VERSION 5.8 ;
BUSBITCHARS "[]" ;
DIVIDERCHAR "/" ;
UNITS
    DATABASE MICRONS 2000 ;
END UNITS

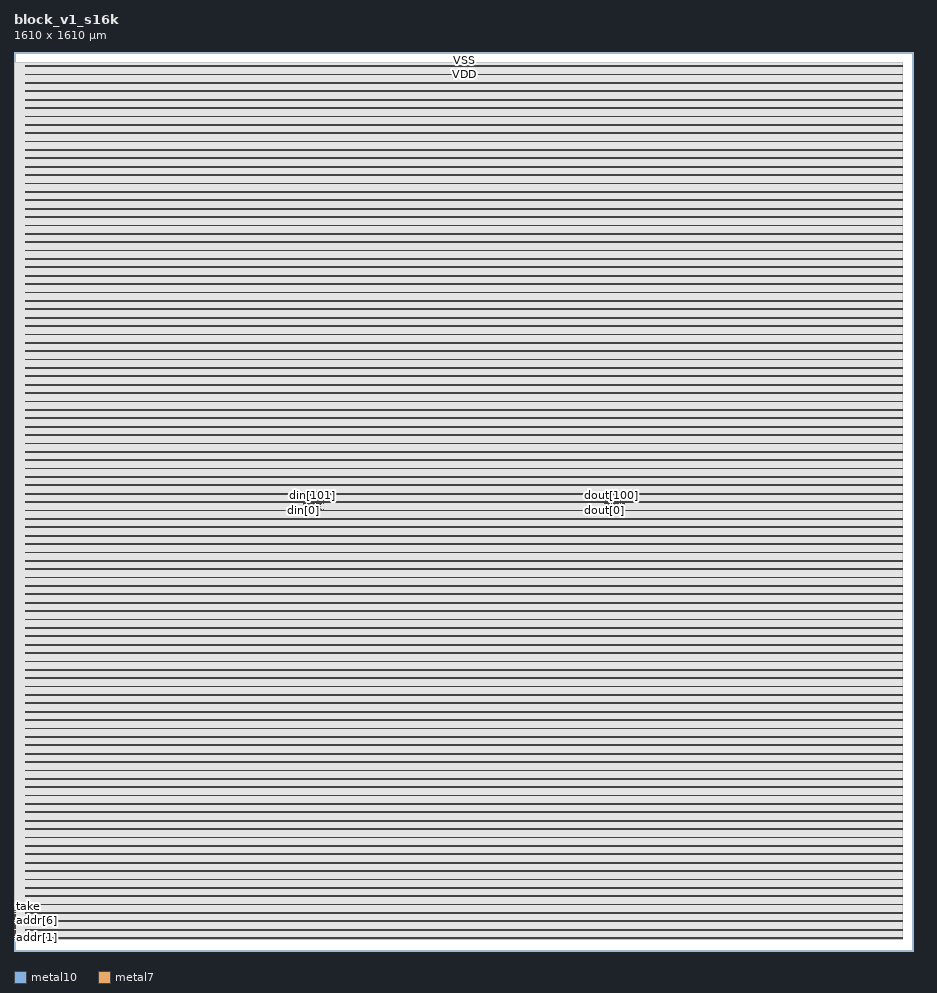
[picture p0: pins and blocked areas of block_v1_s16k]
MACRO block_v1_s16k
  FOREIGN block_v1_s16k 0 0 ;
  CLASS BLOCK ;
  SIZE 1610 BY 1610 ;
  PIN addr[0]
    DIRECTION INPUT ;
    USE SIGNAL ;
    PORT
      LAYER metal10 ;
        RECT  1.295 20.47 2.095 21.27 ;
    END
  END addr[0]
  PIN addr[1]
    DIRECTION INPUT ;
    USE SIGNAL ;
    PORT
      LAYER metal10 ;
        RECT  1.295 23.67 2.095 24.47 ;
    END
  END addr[1]
  PIN addr[2]
    DIRECTION INPUT ;
    USE SIGNAL ;
    PORT
      LAYER metal10 ;
        RECT  1.295 26.87 2.095 27.67 ;
    END
  END addr[2]
  PIN addr[3]
    DIRECTION INPUT ;
    USE SIGNAL ;
    PORT
      LAYER metal10 ;
        RECT  1.295 30.07 2.095 30.87 ;
    END
  END addr[3]
  PIN addr[4]
    DIRECTION INPUT ;
    USE SIGNAL ;
    PORT
      LAYER metal10 ;
        RECT  1.295 33.27 2.095 34.07 ;
    END
  END addr[4]
  PIN addr[5]
    DIRECTION INPUT ;
    USE SIGNAL ;
    PORT
      LAYER metal10 ;
        RECT  1.295 36.47 2.095 37.27 ;
    END
  END addr[5]
  PIN addr[6]
    DIRECTION INPUT ;
    USE SIGNAL ;
    PORT
      LAYER metal10 ;
        RECT  1.295 39.67 2.095 40.47 ;
    END
  END addr[6]
  PIN addr[7]
    DIRECTION INPUT ;
    USE SIGNAL ;
    PORT
      LAYER metal10 ;
        RECT  1.295 42.87 2.095 43.67 ;
    END
  END addr[7]
  PIN addr[8]
    DIRECTION INPUT ;
    USE SIGNAL ;
    PORT
      LAYER metal10 ;
        RECT  1.295 46.07 2.095 46.87 ;
    END
  END addr[8]
  PIN addr[9]
    DIRECTION INPUT ;
    USE SIGNAL ;
    PORT
      LAYER metal10 ;
        RECT  1.295 49.27 2.095 50.07 ;
    END
  END addr[9]
  PIN clk
    DIRECTION INPUT ;
    USE SIGNAL ;
    PORT
      LAYER metal10 ;
        RECT  1.295 52.47 2.095 53.27 ;
    END
  END clk
  PIN din[0]
    DIRECTION INPUT ;
    USE SIGNAL ;
    PORT
      LAYER metal10 ;
        RECT  518.095 788.47 518.895 789.27 ;
    END
  END din[0]
  PIN din[100]
    DIRECTION INPUT ;
    USE SIGNAL ;
    PORT
      LAYER metal10 ;
        RECT  530.895 814.07 531.695 814.87 ;
    END
  END din[100]
  PIN din[101]
    DIRECTION INPUT ;
    USE SIGNAL ;
    PORT
      LAYER metal10 ;
        RECT  534.095 814.07 534.895 814.87 ;
    END
  END din[101]
  PIN din[102]
    DIRECTION INPUT ;
    USE SIGNAL ;
    PORT
      LAYER metal10 ;
        RECT  537.295 814.07 538.095 814.87 ;
    END
  END din[102]
  PIN din[103]
    DIRECTION INPUT ;
    USE SIGNAL ;
    PORT
      LAYER metal10 ;
        RECT  540.495 814.07 541.295 814.87 ;
    END
  END din[103]
  PIN din[104]
    DIRECTION INPUT ;
    USE SIGNAL ;
    PORT
      LAYER metal10 ;
        RECT  543.695 814.07 544.495 814.87 ;
    END
  END din[104]
  PIN din[105]
    DIRECTION INPUT ;
    USE SIGNAL ;
    PORT
      LAYER metal10 ;
        RECT  546.895 814.07 547.695 814.87 ;
    END
  END din[105]
  PIN din[106]
    DIRECTION INPUT ;
    USE SIGNAL ;
    PORT
      LAYER metal10 ;
        RECT  550.095 814.07 550.895 814.87 ;
    END
  END din[106]
  PIN din[107]
    DIRECTION INPUT ;
    USE SIGNAL ;
    PORT
      LAYER metal10 ;
        RECT  553.295 814.07 554.095 814.87 ;
    END
  END din[107]
  PIN din[108]
    DIRECTION INPUT ;
    USE SIGNAL ;
    PORT
      LAYER metal10 ;
        RECT  518.095 817.27 518.895 818.07 ;
    END
  END din[108]
  PIN din[109]
    DIRECTION INPUT ;
    USE SIGNAL ;
    PORT
      LAYER metal10 ;
        RECT  521.295 817.27 522.095 818.07 ;
    END
  END din[109]
  PIN din[10]
    DIRECTION INPUT ;
    USE SIGNAL ;
    PORT
      LAYER metal10 ;
        RECT  550.095 788.47 550.895 789.27 ;
    END
  END din[10]
  PIN din[110]
    DIRECTION INPUT ;
    USE SIGNAL ;
    PORT
      LAYER metal10 ;
        RECT  524.495 817.27 525.295 818.07 ;
    END
  END din[110]
  PIN din[111]
    DIRECTION INPUT ;
    USE SIGNAL ;
    PORT
      LAYER metal10 ;
        RECT  527.695 817.27 528.495 818.07 ;
    END
  END din[111]
  PIN din[112]
    DIRECTION INPUT ;
    USE SIGNAL ;
    PORT
      LAYER metal10 ;
        RECT  530.895 817.27 531.695 818.07 ;
    END
  END din[112]
  PIN din[113]
    DIRECTION INPUT ;
    USE SIGNAL ;
    PORT
      LAYER metal10 ;
        RECT  534.095 817.27 534.895 818.07 ;
    END
  END din[113]
  PIN din[114]
    DIRECTION INPUT ;
    USE SIGNAL ;
    PORT
      LAYER metal10 ;
        RECT  537.295 817.27 538.095 818.07 ;
    END
  END din[114]
  PIN din[115]
    DIRECTION INPUT ;
    USE SIGNAL ;
    PORT
      LAYER metal10 ;
        RECT  540.495 817.27 541.295 818.07 ;
    END
  END din[115]
  PIN din[116]
    DIRECTION INPUT ;
    USE SIGNAL ;
    PORT
      LAYER metal10 ;
        RECT  543.695 817.27 544.495 818.07 ;
    END
  END din[116]
  PIN din[117]
    DIRECTION INPUT ;
    USE SIGNAL ;
    PORT
      LAYER metal10 ;
        RECT  546.895 817.27 547.695 818.07 ;
    END
  END din[117]
  PIN din[118]
    DIRECTION INPUT ;
    USE SIGNAL ;
    PORT
      LAYER metal10 ;
        RECT  550.095 817.27 550.895 818.07 ;
    END
  END din[118]
  PIN din[119]
    DIRECTION INPUT ;
    USE SIGNAL ;
    PORT
      LAYER metal10 ;
        RECT  553.295 817.27 554.095 818.07 ;
    END
  END din[119]
  PIN din[11]
    DIRECTION INPUT ;
    USE SIGNAL ;
    PORT
      LAYER metal10 ;
        RECT  553.295 788.47 554.095 789.27 ;
    END
  END din[11]
  PIN din[120]
    DIRECTION INPUT ;
    USE SIGNAL ;
    PORT
      LAYER metal10 ;
        RECT  518.095 820.47 518.895 821.27 ;
    END
  END din[120]
  PIN din[121]
    DIRECTION INPUT ;
    USE SIGNAL ;
    PORT
      LAYER metal10 ;
        RECT  521.295 820.47 522.095 821.27 ;
    END
  END din[121]
  PIN din[122]
    DIRECTION INPUT ;
    USE SIGNAL ;
    PORT
      LAYER metal10 ;
        RECT  524.495 820.47 525.295 821.27 ;
    END
  END din[122]
  PIN din[123]
    DIRECTION INPUT ;
    USE SIGNAL ;
    PORT
      LAYER metal10 ;
        RECT  527.695 820.47 528.495 821.27 ;
    END
  END din[123]
  PIN din[124]
    DIRECTION INPUT ;
    USE SIGNAL ;
    PORT
      LAYER metal10 ;
        RECT  530.895 820.47 531.695 821.27 ;
    END
  END din[124]
  PIN din[125]
    DIRECTION INPUT ;
    USE SIGNAL ;
    PORT
      LAYER metal10 ;
        RECT  534.095 820.47 534.895 821.27 ;
    END
  END din[125]
  PIN din[126]
    DIRECTION INPUT ;
    USE SIGNAL ;
    PORT
      LAYER metal10 ;
        RECT  537.295 820.47 538.095 821.27 ;
    END
  END din[126]
  PIN din[127]
    DIRECTION INPUT ;
    USE SIGNAL ;
    PORT
      LAYER metal10 ;
        RECT  540.495 820.47 541.295 821.27 ;
    END
  END din[127]
  PIN din[12]
    DIRECTION INPUT ;
    USE SIGNAL ;
    PORT
      LAYER metal10 ;
        RECT  518.095 791.67 518.895 792.47 ;
    END
  END din[12]
  PIN din[13]
    DIRECTION INPUT ;
    USE SIGNAL ;
    PORT
      LAYER metal10 ;
        RECT  521.295 791.67 522.095 792.47 ;
    END
  END din[13]
  PIN din[14]
    DIRECTION INPUT ;
    USE SIGNAL ;
    PORT
      LAYER metal10 ;
        RECT  524.495 791.67 525.295 792.47 ;
    END
  END din[14]
  PIN din[15]
    DIRECTION INPUT ;
    USE SIGNAL ;
    PORT
      LAYER metal10 ;
        RECT  527.695 791.67 528.495 792.47 ;
    END
  END din[15]
  PIN din[16]
    DIRECTION INPUT ;
    USE SIGNAL ;
    PORT
      LAYER metal10 ;
        RECT  530.895 791.67 531.695 792.47 ;
    END
  END din[16]
  PIN din[17]
    DIRECTION INPUT ;
    USE SIGNAL ;
    PORT
      LAYER metal10 ;
        RECT  534.095 791.67 534.895 792.47 ;
    END
  END din[17]
  PIN din[18]
    DIRECTION INPUT ;
    USE SIGNAL ;
    PORT
      LAYER metal10 ;
        RECT  537.295 791.67 538.095 792.47 ;
    END
  END din[18]
  PIN din[19]
    DIRECTION INPUT ;
    USE SIGNAL ;
    PORT
      LAYER metal10 ;
        RECT  540.495 791.67 541.295 792.47 ;
    END
  END din[19]
  PIN din[1]
    DIRECTION INPUT ;
    USE SIGNAL ;
    PORT
      LAYER metal10 ;
        RECT  521.295 788.47 522.095 789.27 ;
    END
  END din[1]
  PIN din[20]
    DIRECTION INPUT ;
    USE SIGNAL ;
    PORT
      LAYER metal10 ;
        RECT  543.695 791.67 544.495 792.47 ;
    END
  END din[20]
  PIN din[21]
    DIRECTION INPUT ;
    USE SIGNAL ;
    PORT
      LAYER metal10 ;
        RECT  546.895 791.67 547.695 792.47 ;
    END
  END din[21]
  PIN din[22]
    DIRECTION INPUT ;
    USE SIGNAL ;
    PORT
      LAYER metal10 ;
        RECT  550.095 791.67 550.895 792.47 ;
    END
  END din[22]
  PIN din[23]
    DIRECTION INPUT ;
    USE SIGNAL ;
    PORT
      LAYER metal10 ;
        RECT  553.295 791.67 554.095 792.47 ;
    END
  END din[23]
  PIN din[24]
    DIRECTION INPUT ;
    USE SIGNAL ;
    PORT
      LAYER metal10 ;
        RECT  518.095 794.87 518.895 795.67 ;
    END
  END din[24]
  PIN din[25]
    DIRECTION INPUT ;
    USE SIGNAL ;
    PORT
      LAYER metal10 ;
        RECT  521.295 794.87 522.095 795.67 ;
    END
  END din[25]
  PIN din[26]
    DIRECTION INPUT ;
    USE SIGNAL ;
    PORT
      LAYER metal10 ;
        RECT  524.495 794.87 525.295 795.67 ;
    END
  END din[26]
  PIN din[27]
    DIRECTION INPUT ;
    USE SIGNAL ;
    PORT
      LAYER metal10 ;
        RECT  527.695 794.87 528.495 795.67 ;
    END
  END din[27]
  PIN din[28]
    DIRECTION INPUT ;
    USE SIGNAL ;
    PORT
      LAYER metal10 ;
        RECT  530.895 794.87 531.695 795.67 ;
    END
  END din[28]
  PIN din[29]
    DIRECTION INPUT ;
    USE SIGNAL ;
    PORT
      LAYER metal10 ;
        RECT  534.095 794.87 534.895 795.67 ;
    END
  END din[29]
  PIN din[2]
    DIRECTION INPUT ;
    USE SIGNAL ;
    PORT
      LAYER metal10 ;
        RECT  524.495 788.47 525.295 789.27 ;
    END
  END din[2]
  PIN din[30]
    DIRECTION INPUT ;
    USE SIGNAL ;
    PORT
      LAYER metal10 ;
        RECT  537.295 794.87 538.095 795.67 ;
    END
  END din[30]
  PIN din[31]
    DIRECTION INPUT ;
    USE SIGNAL ;
    PORT
      LAYER metal10 ;
        RECT  540.495 794.87 541.295 795.67 ;
    END
  END din[31]
  PIN din[32]
    DIRECTION INPUT ;
    USE SIGNAL ;
    PORT
      LAYER metal10 ;
        RECT  543.695 794.87 544.495 795.67 ;
    END
  END din[32]
  PIN din[33]
    DIRECTION INPUT ;
    USE SIGNAL ;
    PORT
      LAYER metal10 ;
        RECT  546.895 794.87 547.695 795.67 ;
    END
  END din[33]
  PIN din[34]
    DIRECTION INPUT ;
    USE SIGNAL ;
    PORT
      LAYER metal10 ;
        RECT  550.095 794.87 550.895 795.67 ;
    END
  END din[34]
  PIN din[35]
    DIRECTION INPUT ;
    USE SIGNAL ;
    PORT
      LAYER metal10 ;
        RECT  553.295 794.87 554.095 795.67 ;
    END
  END din[35]
  PIN din[36]
    DIRECTION INPUT ;
    USE SIGNAL ;
    PORT
      LAYER metal10 ;
        RECT  518.095 798.07 518.895 798.87 ;
    END
  END din[36]
  PIN din[37]
    DIRECTION INPUT ;
    USE SIGNAL ;
    PORT
      LAYER metal10 ;
        RECT  521.295 798.07 522.095 798.87 ;
    END
  END din[37]
  PIN din[38]
    DIRECTION INPUT ;
    USE SIGNAL ;
    PORT
      LAYER metal10 ;
        RECT  524.495 798.07 525.295 798.87 ;
    END
  END din[38]
  PIN din[39]
    DIRECTION INPUT ;
    USE SIGNAL ;
    PORT
      LAYER metal10 ;
        RECT  527.695 798.07 528.495 798.87 ;
    END
  END din[39]
  PIN din[3]
    DIRECTION INPUT ;
    USE SIGNAL ;
    PORT
      LAYER metal10 ;
        RECT  527.695 788.47 528.495 789.27 ;
    END
  END din[3]
  PIN din[40]
    DIRECTION INPUT ;
    USE SIGNAL ;
    PORT
      LAYER metal10 ;
        RECT  530.895 798.07 531.695 798.87 ;
    END
  END din[40]
  PIN din[41]
    DIRECTION INPUT ;
    USE SIGNAL ;
    PORT
      LAYER metal10 ;
        RECT  534.095 798.07 534.895 798.87 ;
    END
  END din[41]
  PIN din[42]
    DIRECTION INPUT ;
    USE SIGNAL ;
    PORT
      LAYER metal10 ;
        RECT  537.295 798.07 538.095 798.87 ;
    END
  END din[42]
  PIN din[43]
    DIRECTION INPUT ;
    USE SIGNAL ;
    PORT
      LAYER metal10 ;
        RECT  540.495 798.07 541.295 798.87 ;
    END
  END din[43]
  PIN din[44]
    DIRECTION INPUT ;
    USE SIGNAL ;
    PORT
      LAYER metal10 ;
        RECT  543.695 798.07 544.495 798.87 ;
    END
  END din[44]
  PIN din[45]
    DIRECTION INPUT ;
    USE SIGNAL ;
    PORT
      LAYER metal10 ;
        RECT  546.895 798.07 547.695 798.87 ;
    END
  END din[45]
  PIN din[46]
    DIRECTION INPUT ;
    USE SIGNAL ;
    PORT
      LAYER metal10 ;
        RECT  550.095 798.07 550.895 798.87 ;
    END
  END din[46]
  PIN din[47]
    DIRECTION INPUT ;
    USE SIGNAL ;
    PORT
      LAYER metal10 ;
        RECT  553.295 798.07 554.095 798.87 ;
    END
  END din[47]
  PIN din[48]
    DIRECTION INPUT ;
    USE SIGNAL ;
    PORT
      LAYER metal10 ;
        RECT  518.095 801.27 518.895 802.07 ;
    END
  END din[48]
  PIN din[49]
    DIRECTION INPUT ;
    USE SIGNAL ;
    PORT
      LAYER metal10 ;
        RECT  521.295 801.27 522.095 802.07 ;
    END
  END din[49]
  PIN din[4]
    DIRECTION INPUT ;
    USE SIGNAL ;
    PORT
      LAYER metal10 ;
        RECT  530.895 788.47 531.695 789.27 ;
    END
  END din[4]
  PIN din[50]
    DIRECTION INPUT ;
    USE SIGNAL ;
    PORT
      LAYER metal10 ;
        RECT  524.495 801.27 525.295 802.07 ;
    END
  END din[50]
  PIN din[51]
    DIRECTION INPUT ;
    USE SIGNAL ;
    PORT
      LAYER metal10 ;
        RECT  527.695 801.27 528.495 802.07 ;
    END
  END din[51]
  PIN din[52]
    DIRECTION INPUT ;
    USE SIGNAL ;
    PORT
      LAYER metal10 ;
        RECT  530.895 801.27 531.695 802.07 ;
    END
  END din[52]
  PIN din[53]
    DIRECTION INPUT ;
    USE SIGNAL ;
    PORT
      LAYER metal10 ;
        RECT  534.095 801.27 534.895 802.07 ;
    END
  END din[53]
  PIN din[54]
    DIRECTION INPUT ;
    USE SIGNAL ;
    PORT
      LAYER metal10 ;
        RECT  537.295 801.27 538.095 802.07 ;
    END
  END din[54]
  PIN din[55]
    DIRECTION INPUT ;
    USE SIGNAL ;
    PORT
      LAYER metal10 ;
        RECT  540.495 801.27 541.295 802.07 ;
    END
  END din[55]
  PIN din[56]
    DIRECTION INPUT ;
    USE SIGNAL ;
    PORT
      LAYER metal10 ;
        RECT  543.695 801.27 544.495 802.07 ;
    END
  END din[56]
  PIN din[57]
    DIRECTION INPUT ;
    USE SIGNAL ;
    PORT
      LAYER metal10 ;
        RECT  546.895 801.27 547.695 802.07 ;
    END
  END din[57]
  PIN din[58]
    DIRECTION INPUT ;
    USE SIGNAL ;
    PORT
      LAYER metal10 ;
        RECT  550.095 801.27 550.895 802.07 ;
    END
  END din[58]
  PIN din[59]
    DIRECTION INPUT ;
    USE SIGNAL ;
    PORT
      LAYER metal10 ;
        RECT  553.295 801.27 554.095 802.07 ;
    END
  END din[59]
  PIN din[5]
    DIRECTION INPUT ;
    USE SIGNAL ;
    PORT
      LAYER metal10 ;
        RECT  534.095 788.47 534.895 789.27 ;
    END
  END din[5]
  PIN din[60]
    DIRECTION INPUT ;
    USE SIGNAL ;
    PORT
      LAYER metal10 ;
        RECT  518.095 804.47 518.895 805.27 ;
    END
  END din[60]
  PIN din[61]
    DIRECTION INPUT ;
    USE SIGNAL ;
    PORT
      LAYER metal10 ;
        RECT  521.295 804.47 522.095 805.27 ;
    END
  END din[61]
  PIN din[62]
    DIRECTION INPUT ;
    USE SIGNAL ;
    PORT
      LAYER metal10 ;
        RECT  524.495 804.47 525.295 805.27 ;
    END
  END din[62]
  PIN din[63]
    DIRECTION INPUT ;
    USE SIGNAL ;
    PORT
      LAYER metal10 ;
        RECT  527.695 804.47 528.495 805.27 ;
    END
  END din[63]
  PIN din[64]
    DIRECTION INPUT ;
    USE SIGNAL ;
    PORT
      LAYER metal10 ;
        RECT  530.895 804.47 531.695 805.27 ;
    END
  END din[64]
  PIN din[65]
    DIRECTION INPUT ;
    USE SIGNAL ;
    PORT
      LAYER metal10 ;
        RECT  534.095 804.47 534.895 805.27 ;
    END
  END din[65]
  PIN din[66]
    DIRECTION INPUT ;
    USE SIGNAL ;
    PORT
      LAYER metal10 ;
        RECT  537.295 804.47 538.095 805.27 ;
    END
  END din[66]
  PIN din[67]
    DIRECTION INPUT ;
    USE SIGNAL ;
    PORT
      LAYER metal10 ;
        RECT  540.495 804.47 541.295 805.27 ;
    END
  END din[67]
  PIN din[68]
    DIRECTION INPUT ;
    USE SIGNAL ;
    PORT
      LAYER metal10 ;
        RECT  543.695 804.47 544.495 805.27 ;
    END
  END din[68]
  PIN din[69]
    DIRECTION INPUT ;
    USE SIGNAL ;
    PORT
      LAYER metal10 ;
        RECT  546.895 804.47 547.695 805.27 ;
    END
  END din[69]
  PIN din[6]
    DIRECTION INPUT ;
    USE SIGNAL ;
    PORT
      LAYER metal10 ;
        RECT  537.295 788.47 538.095 789.27 ;
    END
  END din[6]
  PIN din[70]
    DIRECTION INPUT ;
    USE SIGNAL ;
    PORT
      LAYER metal10 ;
        RECT  550.095 804.47 550.895 805.27 ;
    END
  END din[70]
  PIN din[71]
    DIRECTION INPUT ;
    USE SIGNAL ;
    PORT
      LAYER metal10 ;
        RECT  553.295 804.47 554.095 805.27 ;
    END
  END din[71]
  PIN din[72]
    DIRECTION INPUT ;
    USE SIGNAL ;
    PORT
      LAYER metal10 ;
        RECT  518.095 807.67 518.895 808.47 ;
    END
  END din[72]
  PIN din[73]
    DIRECTION INPUT ;
    USE SIGNAL ;
    PORT
      LAYER metal10 ;
        RECT  521.295 807.67 522.095 808.47 ;
    END
  END din[73]
  PIN din[74]
    DIRECTION INPUT ;
    USE SIGNAL ;
    PORT
      LAYER metal10 ;
        RECT  524.495 807.67 525.295 808.47 ;
    END
  END din[74]
  PIN din[75]
    DIRECTION INPUT ;
    USE SIGNAL ;
    PORT
      LAYER metal10 ;
        RECT  527.695 807.67 528.495 808.47 ;
    END
  END din[75]
  PIN din[76]
    DIRECTION INPUT ;
    USE SIGNAL ;
    PORT
      LAYER metal10 ;
        RECT  530.895 807.67 531.695 808.47 ;
    END
  END din[76]
  PIN din[77]
    DIRECTION INPUT ;
    USE SIGNAL ;
    PORT
      LAYER metal10 ;
        RECT  534.095 807.67 534.895 808.47 ;
    END
  END din[77]
  PIN din[78]
    DIRECTION INPUT ;
    USE SIGNAL ;
    PORT
      LAYER metal10 ;
        RECT  537.295 807.67 538.095 808.47 ;
    END
  END din[78]
  PIN din[79]
    DIRECTION INPUT ;
    USE SIGNAL ;
    PORT
      LAYER metal10 ;
        RECT  540.495 807.67 541.295 808.47 ;
    END
  END din[79]
  PIN din[7]
    DIRECTION INPUT ;
    USE SIGNAL ;
    PORT
      LAYER metal10 ;
        RECT  540.495 788.47 541.295 789.27 ;
    END
  END din[7]
  PIN din[80]
    DIRECTION INPUT ;
    USE SIGNAL ;
    PORT
      LAYER metal10 ;
        RECT  543.695 807.67 544.495 808.47 ;
    END
  END din[80]
  PIN din[81]
    DIRECTION INPUT ;
    USE SIGNAL ;
    PORT
      LAYER metal10 ;
        RECT  546.895 807.67 547.695 808.47 ;
    END
  END din[81]
  PIN din[82]
    DIRECTION INPUT ;
    USE SIGNAL ;
    PORT
      LAYER metal10 ;
        RECT  550.095 807.67 550.895 808.47 ;
    END
  END din[82]
  PIN din[83]
    DIRECTION INPUT ;
    USE SIGNAL ;
    PORT
      LAYER metal10 ;
        RECT  553.295 807.67 554.095 808.47 ;
    END
  END din[83]
  PIN din[84]
    DIRECTION INPUT ;
    USE SIGNAL ;
    PORT
      LAYER metal10 ;
        RECT  518.095 810.87 518.895 811.67 ;
    END
  END din[84]
  PIN din[85]
    DIRECTION INPUT ;
    USE SIGNAL ;
    PORT
      LAYER metal10 ;
        RECT  521.295 810.87 522.095 811.67 ;
    END
  END din[85]
  PIN din[86]
    DIRECTION INPUT ;
    USE SIGNAL ;
    PORT
      LAYER metal10 ;
        RECT  524.495 810.87 525.295 811.67 ;
    END
  END din[86]
  PIN din[87]
    DIRECTION INPUT ;
    USE SIGNAL ;
    PORT
      LAYER metal10 ;
        RECT  527.695 810.87 528.495 811.67 ;
    END
  END din[87]
  PIN din[88]
    DIRECTION INPUT ;
    USE SIGNAL ;
    PORT
      LAYER metal10 ;
        RECT  530.895 810.87 531.695 811.67 ;
    END
  END din[88]
  PIN din[89]
    DIRECTION INPUT ;
    USE SIGNAL ;
    PORT
      LAYER metal10 ;
        RECT  534.095 810.87 534.895 811.67 ;
    END
  END din[89]
  PIN din[8]
    DIRECTION INPUT ;
    USE SIGNAL ;
    PORT
      LAYER metal10 ;
        RECT  543.695 788.47 544.495 789.27 ;
    END
  END din[8]
  PIN din[90]
    DIRECTION INPUT ;
    USE SIGNAL ;
    PORT
      LAYER metal10 ;
        RECT  537.295 810.87 538.095 811.67 ;
    END
  END din[90]
  PIN din[91]
    DIRECTION INPUT ;
    USE SIGNAL ;
    PORT
      LAYER metal10 ;
        RECT  540.495 810.87 541.295 811.67 ;
    END
  END din[91]
  PIN din[92]
    DIRECTION INPUT ;
    USE SIGNAL ;
    PORT
      LAYER metal10 ;
        RECT  543.695 810.87 544.495 811.67 ;
    END
  END din[92]
  PIN din[93]
    DIRECTION INPUT ;
    USE SIGNAL ;
    PORT
      LAYER metal10 ;
        RECT  546.895 810.87 547.695 811.67 ;
    END
  END din[93]
  PIN din[94]
    DIRECTION INPUT ;
    USE SIGNAL ;
    PORT
      LAYER metal10 ;
        RECT  550.095 810.87 550.895 811.67 ;
    END
  END din[94]
  PIN din[95]
    DIRECTION INPUT ;
    USE SIGNAL ;
    PORT
      LAYER metal10 ;
        RECT  553.295 810.87 554.095 811.67 ;
    END
  END din[95]
  PIN din[96]
    DIRECTION INPUT ;
    USE SIGNAL ;
    PORT
      LAYER metal10 ;
        RECT  518.095 814.07 518.895 814.87 ;
    END
  END din[96]
  PIN din[97]
    DIRECTION INPUT ;
    USE SIGNAL ;
    PORT
      LAYER metal10 ;
        RECT  521.295 814.07 522.095 814.87 ;
    END
  END din[97]
  PIN din[98]
    DIRECTION INPUT ;
    USE SIGNAL ;
    PORT
      LAYER metal10 ;
        RECT  524.495 814.07 525.295 814.87 ;
    END
  END din[98]
  PIN din[99]
    DIRECTION INPUT ;
    USE SIGNAL ;
    PORT
      LAYER metal10 ;
        RECT  527.695 814.07 528.495 814.87 ;
    END
  END din[99]
  PIN din[9]
    DIRECTION INPUT ;
    USE SIGNAL ;
    PORT
      LAYER metal10 ;
        RECT  546.895 788.47 547.695 789.27 ;
    END
  END din[9]
  PIN dout[0]
    DIRECTION OUTPUT ;
    USE SIGNAL ;
    PORT
      LAYER metal10 ;
        RECT  1055.7 788.47 1056.5 789.27 ;
    END
  END dout[0]
  PIN dout[100]
    DIRECTION OUTPUT ;
    USE SIGNAL ;
    PORT
      LAYER metal10 ;
        RECT  1068.49 814.07 1069.29 814.87 ;
    END
  END dout[100]
  PIN dout[101]
    DIRECTION OUTPUT ;
    USE SIGNAL ;
    PORT
      LAYER metal10 ;
        RECT  1071.7 814.07 1072.5 814.87 ;
    END
  END dout[101]
  PIN dout[102]
    DIRECTION OUTPUT ;
    USE SIGNAL ;
    PORT
      LAYER metal10 ;
        RECT  1074.9 814.07 1075.7 814.87 ;
    END
  END dout[102]
  PIN dout[103]
    DIRECTION OUTPUT ;
    USE SIGNAL ;
    PORT
      LAYER metal10 ;
        RECT  1078.09 814.07 1078.89 814.87 ;
    END
  END dout[103]
  PIN dout[104]
    DIRECTION OUTPUT ;
    USE SIGNAL ;
    PORT
      LAYER metal10 ;
        RECT  1081.29 814.07 1082.09 814.87 ;
    END
  END dout[104]
  PIN dout[105]
    DIRECTION OUTPUT ;
    USE SIGNAL ;
    PORT
      LAYER metal10 ;
        RECT  1084.49 814.07 1085.29 814.87 ;
    END
  END dout[105]
  PIN dout[106]
    DIRECTION OUTPUT ;
    USE SIGNAL ;
    PORT
      LAYER metal10 ;
        RECT  1087.7 814.07 1088.5 814.87 ;
    END
  END dout[106]
  PIN dout[107]
    DIRECTION OUTPUT ;
    USE SIGNAL ;
    PORT
      LAYER metal10 ;
        RECT  1090.9 814.07 1091.7 814.87 ;
    END
  END dout[107]
  PIN dout[108]
    DIRECTION OUTPUT ;
    USE SIGNAL ;
    PORT
      LAYER metal10 ;
        RECT  1055.7 817.27 1056.5 818.07 ;
    END
  END dout[108]
  PIN dout[109]
    DIRECTION OUTPUT ;
    USE SIGNAL ;
    PORT
      LAYER metal10 ;
        RECT  1058.9 817.27 1059.7 818.07 ;
    END
  END dout[109]
  PIN dout[10]
    DIRECTION OUTPUT ;
    USE SIGNAL ;
    PORT
      LAYER metal10 ;
        RECT  1087.7 788.47 1088.5 789.27 ;
    END
  END dout[10]
  PIN dout[110]
    DIRECTION OUTPUT ;
    USE SIGNAL ;
    PORT
      LAYER metal10 ;
        RECT  1062.09 817.27 1062.89 818.07 ;
    END
  END dout[110]
  PIN dout[111]
    DIRECTION OUTPUT ;
    USE SIGNAL ;
    PORT
      LAYER metal10 ;
        RECT  1065.29 817.27 1066.09 818.07 ;
    END
  END dout[111]
  PIN dout[112]
    DIRECTION OUTPUT ;
    USE SIGNAL ;
    PORT
      LAYER metal10 ;
        RECT  1068.49 817.27 1069.29 818.07 ;
    END
  END dout[112]
  PIN dout[113]
    DIRECTION OUTPUT ;
    USE SIGNAL ;
    PORT
      LAYER metal10 ;
        RECT  1071.7 817.27 1072.5 818.07 ;
    END
  END dout[113]
  PIN dout[114]
    DIRECTION OUTPUT ;
    USE SIGNAL ;
    PORT
      LAYER metal10 ;
        RECT  1074.9 817.27 1075.7 818.07 ;
    END
  END dout[114]
  PIN dout[115]
    DIRECTION OUTPUT ;
    USE SIGNAL ;
    PORT
      LAYER metal10 ;
        RECT  1078.09 817.27 1078.89 818.07 ;
    END
  END dout[115]
  PIN dout[116]
    DIRECTION OUTPUT ;
    USE SIGNAL ;
    PORT
      LAYER metal10 ;
        RECT  1081.29 817.27 1082.09 818.07 ;
    END
  END dout[116]
  PIN dout[117]
    DIRECTION OUTPUT ;
    USE SIGNAL ;
    PORT
      LAYER metal10 ;
        RECT  1084.49 817.27 1085.29 818.07 ;
    END
  END dout[117]
  PIN dout[118]
    DIRECTION OUTPUT ;
    USE SIGNAL ;
    PORT
      LAYER metal10 ;
        RECT  1087.7 817.27 1088.5 818.07 ;
    END
  END dout[118]
  PIN dout[119]
    DIRECTION OUTPUT ;
    USE SIGNAL ;
    PORT
      LAYER metal10 ;
        RECT  1090.9 817.27 1091.7 818.07 ;
    END
  END dout[119]
  PIN dout[11]
    DIRECTION OUTPUT ;
    USE SIGNAL ;
    PORT
      LAYER metal10 ;
        RECT  1090.9 788.47 1091.7 789.27 ;
    END
  END dout[11]
  PIN dout[120]
    DIRECTION OUTPUT ;
    USE SIGNAL ;
    PORT
      LAYER metal10 ;
        RECT  1055.7 820.47 1056.5 821.27 ;
    END
  END dout[120]
  PIN dout[121]
    DIRECTION OUTPUT ;
    USE SIGNAL ;
    PORT
      LAYER metal10 ;
        RECT  1058.9 820.47 1059.7 821.27 ;
    END
  END dout[121]
  PIN dout[122]
    DIRECTION OUTPUT ;
    USE SIGNAL ;
    PORT
      LAYER metal10 ;
        RECT  1062.09 820.47 1062.89 821.27 ;
    END
  END dout[122]
  PIN dout[123]
    DIRECTION OUTPUT ;
    USE SIGNAL ;
    PORT
      LAYER metal10 ;
        RECT  1065.29 820.47 1066.09 821.27 ;
    END
  END dout[123]
  PIN dout[124]
    DIRECTION OUTPUT ;
    USE SIGNAL ;
    PORT
      LAYER metal10 ;
        RECT  1068.49 820.47 1069.29 821.27 ;
    END
  END dout[124]
  PIN dout[125]
    DIRECTION OUTPUT ;
    USE SIGNAL ;
    PORT
      LAYER metal10 ;
        RECT  1071.7 820.47 1072.5 821.27 ;
    END
  END dout[125]
  PIN dout[126]
    DIRECTION OUTPUT ;
    USE SIGNAL ;
    PORT
      LAYER metal10 ;
        RECT  1074.9 820.47 1075.7 821.27 ;
    END
  END dout[126]
  PIN dout[127]
    DIRECTION OUTPUT ;
    USE SIGNAL ;
    PORT
      LAYER metal10 ;
        RECT  1078.09 820.47 1078.89 821.27 ;
    END
  END dout[127]
  PIN dout[12]
    DIRECTION OUTPUT ;
    USE SIGNAL ;
    PORT
      LAYER metal10 ;
        RECT  1055.7 791.67 1056.5 792.47 ;
    END
  END dout[12]
  PIN dout[13]
    DIRECTION OUTPUT ;
    USE SIGNAL ;
    PORT
      LAYER metal10 ;
        RECT  1058.9 791.67 1059.7 792.47 ;
    END
  END dout[13]
  PIN dout[14]
    DIRECTION OUTPUT ;
    USE SIGNAL ;
    PORT
      LAYER metal10 ;
        RECT  1062.09 791.67 1062.89 792.47 ;
    END
  END dout[14]
  PIN dout[15]
    DIRECTION OUTPUT ;
    USE SIGNAL ;
    PORT
      LAYER metal10 ;
        RECT  1065.29 791.67 1066.09 792.47 ;
    END
  END dout[15]
  PIN dout[16]
    DIRECTION OUTPUT ;
    USE SIGNAL ;
    PORT
      LAYER metal10 ;
        RECT  1068.49 791.67 1069.29 792.47 ;
    END
  END dout[16]
  PIN dout[17]
    DIRECTION OUTPUT ;
    USE SIGNAL ;
    PORT
      LAYER metal10 ;
        RECT  1071.7 791.67 1072.5 792.47 ;
    END
  END dout[17]
  PIN dout[18]
    DIRECTION OUTPUT ;
    USE SIGNAL ;
    PORT
      LAYER metal10 ;
        RECT  1074.9 791.67 1075.7 792.47 ;
    END
  END dout[18]
  PIN dout[19]
    DIRECTION OUTPUT ;
    USE SIGNAL ;
    PORT
      LAYER metal10 ;
        RECT  1078.09 791.67 1078.89 792.47 ;
    END
  END dout[19]
  PIN dout[1]
    DIRECTION OUTPUT ;
    USE SIGNAL ;
    PORT
      LAYER metal10 ;
        RECT  1058.9 788.47 1059.7 789.27 ;
    END
  END dout[1]
  PIN dout[20]
    DIRECTION OUTPUT ;
    USE SIGNAL ;
    PORT
      LAYER metal10 ;
        RECT  1081.29 791.67 1082.09 792.47 ;
    END
  END dout[20]
  PIN dout[21]
    DIRECTION OUTPUT ;
    USE SIGNAL ;
    PORT
      LAYER metal10 ;
        RECT  1084.49 791.67 1085.29 792.47 ;
    END
  END dout[21]
  PIN dout[22]
    DIRECTION OUTPUT ;
    USE SIGNAL ;
    PORT
      LAYER metal10 ;
        RECT  1087.7 791.67 1088.5 792.47 ;
    END
  END dout[22]
  PIN dout[23]
    DIRECTION OUTPUT ;
    USE SIGNAL ;
    PORT
      LAYER metal10 ;
        RECT  1090.9 791.67 1091.7 792.47 ;
    END
  END dout[23]
  PIN dout[24]
    DIRECTION OUTPUT ;
    USE SIGNAL ;
    PORT
      LAYER metal10 ;
        RECT  1055.7 794.87 1056.5 795.67 ;
    END
  END dout[24]
  PIN dout[25]
    DIRECTION OUTPUT ;
    USE SIGNAL ;
    PORT
      LAYER metal10 ;
        RECT  1058.9 794.87 1059.7 795.67 ;
    END
  END dout[25]
  PIN dout[26]
    DIRECTION OUTPUT ;
    USE SIGNAL ;
    PORT
      LAYER metal10 ;
        RECT  1062.09 794.87 1062.89 795.67 ;
    END
  END dout[26]
  PIN dout[27]
    DIRECTION OUTPUT ;
    USE SIGNAL ;
    PORT
      LAYER metal10 ;
        RECT  1065.29 794.87 1066.09 795.67 ;
    END
  END dout[27]
  PIN dout[28]
    DIRECTION OUTPUT ;
    USE SIGNAL ;
    PORT
      LAYER metal10 ;
        RECT  1068.49 794.87 1069.29 795.67 ;
    END
  END dout[28]
  PIN dout[29]
    DIRECTION OUTPUT ;
    USE SIGNAL ;
    PORT
      LAYER metal10 ;
        RECT  1071.7 794.87 1072.5 795.67 ;
    END
  END dout[29]
  PIN dout[2]
    DIRECTION OUTPUT ;
    USE SIGNAL ;
    PORT
      LAYER metal10 ;
        RECT  1062.09 788.47 1062.89 789.27 ;
    END
  END dout[2]
  PIN dout[30]
    DIRECTION OUTPUT ;
    USE SIGNAL ;
    PORT
      LAYER metal10 ;
        RECT  1074.9 794.87 1075.7 795.67 ;
    END
  END dout[30]
  PIN dout[31]
    DIRECTION OUTPUT ;
    USE SIGNAL ;
    PORT
      LAYER metal10 ;
        RECT  1078.09 794.87 1078.89 795.67 ;
    END
  END dout[31]
  PIN dout[32]
    DIRECTION OUTPUT ;
    USE SIGNAL ;
    PORT
      LAYER metal10 ;
        RECT  1081.29 794.87 1082.09 795.67 ;
    END
  END dout[32]
  PIN dout[33]
    DIRECTION OUTPUT ;
    USE SIGNAL ;
    PORT
      LAYER metal10 ;
        RECT  1084.49 794.87 1085.29 795.67 ;
    END
  END dout[33]
  PIN dout[34]
    DIRECTION OUTPUT ;
    USE SIGNAL ;
    PORT
      LAYER metal10 ;
        RECT  1087.7 794.87 1088.5 795.67 ;
    END
  END dout[34]
  PIN dout[35]
    DIRECTION OUTPUT ;
    USE SIGNAL ;
    PORT
      LAYER metal10 ;
        RECT  1090.9 794.87 1091.7 795.67 ;
    END
  END dout[35]
  PIN dout[36]
    DIRECTION OUTPUT ;
    USE SIGNAL ;
    PORT
      LAYER metal10 ;
        RECT  1055.7 798.07 1056.5 798.87 ;
    END
  END dout[36]
  PIN dout[37]
    DIRECTION OUTPUT ;
    USE SIGNAL ;
    PORT
      LAYER metal10 ;
        RECT  1058.9 798.07 1059.7 798.87 ;
    END
  END dout[37]
  PIN dout[38]
    DIRECTION OUTPUT ;
    USE SIGNAL ;
    PORT
      LAYER metal10 ;
        RECT  1062.09 798.07 1062.89 798.87 ;
    END
  END dout[38]
  PIN dout[39]
    DIRECTION OUTPUT ;
    USE SIGNAL ;
    PORT
      LAYER metal10 ;
        RECT  1065.29 798.07 1066.09 798.87 ;
    END
  END dout[39]
  PIN dout[3]
    DIRECTION OUTPUT ;
    USE SIGNAL ;
    PORT
      LAYER metal10 ;
        RECT  1065.29 788.47 1066.09 789.27 ;
    END
  END dout[3]
  PIN dout[40]
    DIRECTION OUTPUT ;
    USE SIGNAL ;
    PORT
      LAYER metal10 ;
        RECT  1068.49 798.07 1069.29 798.87 ;
    END
  END dout[40]
  PIN dout[41]
    DIRECTION OUTPUT ;
    USE SIGNAL ;
    PORT
      LAYER metal10 ;
        RECT  1071.7 798.07 1072.5 798.87 ;
    END
  END dout[41]
  PIN dout[42]
    DIRECTION OUTPUT ;
    USE SIGNAL ;
    PORT
      LAYER metal10 ;
        RECT  1074.9 798.07 1075.7 798.87 ;
    END
  END dout[42]
  PIN dout[43]
    DIRECTION OUTPUT ;
    USE SIGNAL ;
    PORT
      LAYER metal10 ;
        RECT  1078.09 798.07 1078.89 798.87 ;
    END
  END dout[43]
  PIN dout[44]
    DIRECTION OUTPUT ;
    USE SIGNAL ;
    PORT
      LAYER metal10 ;
        RECT  1081.29 798.07 1082.09 798.87 ;
    END
  END dout[44]
  PIN dout[45]
    DIRECTION OUTPUT ;
    USE SIGNAL ;
    PORT
      LAYER metal10 ;
        RECT  1084.49 798.07 1085.29 798.87 ;
    END
  END dout[45]
  PIN dout[46]
    DIRECTION OUTPUT ;
    USE SIGNAL ;
    PORT
      LAYER metal10 ;
        RECT  1087.7 798.07 1088.5 798.87 ;
    END
  END dout[46]
  PIN dout[47]
    DIRECTION OUTPUT ;
    USE SIGNAL ;
    PORT
      LAYER metal10 ;
        RECT  1090.9 798.07 1091.7 798.87 ;
    END
  END dout[47]
  PIN dout[48]
    DIRECTION OUTPUT ;
    USE SIGNAL ;
    PORT
      LAYER metal10 ;
        RECT  1055.7 801.27 1056.5 802.07 ;
    END
  END dout[48]
  PIN dout[49]
    DIRECTION OUTPUT ;
    USE SIGNAL ;
    PORT
      LAYER metal10 ;
        RECT  1058.9 801.27 1059.7 802.07 ;
    END
  END dout[49]
  PIN dout[4]
    DIRECTION OUTPUT ;
    USE SIGNAL ;
    PORT
      LAYER metal10 ;
        RECT  1068.49 788.47 1069.29 789.27 ;
    END
  END dout[4]
  PIN dout[50]
    DIRECTION OUTPUT ;
    USE SIGNAL ;
    PORT
      LAYER metal10 ;
        RECT  1062.09 801.27 1062.89 802.07 ;
    END
  END dout[50]
  PIN dout[51]
    DIRECTION OUTPUT ;
    USE SIGNAL ;
    PORT
      LAYER metal10 ;
        RECT  1065.29 801.27 1066.09 802.07 ;
    END
  END dout[51]
  PIN dout[52]
    DIRECTION OUTPUT ;
    USE SIGNAL ;
    PORT
      LAYER metal10 ;
        RECT  1068.49 801.27 1069.29 802.07 ;
    END
  END dout[52]
  PIN dout[53]
    DIRECTION OUTPUT ;
    USE SIGNAL ;
    PORT
      LAYER metal10 ;
        RECT  1071.7 801.27 1072.5 802.07 ;
    END
  END dout[53]
  PIN dout[54]
    DIRECTION OUTPUT ;
    USE SIGNAL ;
    PORT
      LAYER metal10 ;
        RECT  1074.9 801.27 1075.7 802.07 ;
    END
  END dout[54]
  PIN dout[55]
    DIRECTION OUTPUT ;
    USE SIGNAL ;
    PORT
      LAYER metal10 ;
        RECT  1078.09 801.27 1078.89 802.07 ;
    END
  END dout[55]
  PIN dout[56]
    DIRECTION OUTPUT ;
    USE SIGNAL ;
    PORT
      LAYER metal10 ;
        RECT  1081.29 801.27 1082.09 802.07 ;
    END
  END dout[56]
  PIN dout[57]
    DIRECTION OUTPUT ;
    USE SIGNAL ;
    PORT
      LAYER metal10 ;
        RECT  1084.49 801.27 1085.29 802.07 ;
    END
  END dout[57]
  PIN dout[58]
    DIRECTION OUTPUT ;
    USE SIGNAL ;
    PORT
      LAYER metal10 ;
        RECT  1087.7 801.27 1088.5 802.07 ;
    END
  END dout[58]
  PIN dout[59]
    DIRECTION OUTPUT ;
    USE SIGNAL ;
    PORT
      LAYER metal10 ;
        RECT  1090.9 801.27 1091.7 802.07 ;
    END
  END dout[59]
  PIN dout[5]
    DIRECTION OUTPUT ;
    USE SIGNAL ;
    PORT
      LAYER metal10 ;
        RECT  1071.7 788.47 1072.5 789.27 ;
    END
  END dout[5]
  PIN dout[60]
    DIRECTION OUTPUT ;
    USE SIGNAL ;
    PORT
      LAYER metal10 ;
        RECT  1055.7 804.47 1056.5 805.27 ;
    END
  END dout[60]
  PIN dout[61]
    DIRECTION OUTPUT ;
    USE SIGNAL ;
    PORT
      LAYER metal10 ;
        RECT  1058.9 804.47 1059.7 805.27 ;
    END
  END dout[61]
  PIN dout[62]
    DIRECTION OUTPUT ;
    USE SIGNAL ;
    PORT
      LAYER metal10 ;
        RECT  1062.09 804.47 1062.89 805.27 ;
    END
  END dout[62]
  PIN dout[63]
    DIRECTION OUTPUT ;
    USE SIGNAL ;
    PORT
      LAYER metal10 ;
        RECT  1065.29 804.47 1066.09 805.27 ;
    END
  END dout[63]
  PIN dout[64]
    DIRECTION OUTPUT ;
    USE SIGNAL ;
    PORT
      LAYER metal10 ;
        RECT  1068.49 804.47 1069.29 805.27 ;
    END
  END dout[64]
  PIN dout[65]
    DIRECTION OUTPUT ;
    USE SIGNAL ;
    PORT
      LAYER metal10 ;
        RECT  1071.7 804.47 1072.5 805.27 ;
    END
  END dout[65]
  PIN dout[66]
    DIRECTION OUTPUT ;
    USE SIGNAL ;
    PORT
      LAYER metal10 ;
        RECT  1074.9 804.47 1075.7 805.27 ;
    END
  END dout[66]
  PIN dout[67]
    DIRECTION OUTPUT ;
    USE SIGNAL ;
    PORT
      LAYER metal10 ;
        RECT  1078.09 804.47 1078.89 805.27 ;
    END
  END dout[67]
  PIN dout[68]
    DIRECTION OUTPUT ;
    USE SIGNAL ;
    PORT
      LAYER metal10 ;
        RECT  1081.29 804.47 1082.09 805.27 ;
    END
  END dout[68]
  PIN dout[69]
    DIRECTION OUTPUT ;
    USE SIGNAL ;
    PORT
      LAYER metal10 ;
        RECT  1084.49 804.47 1085.29 805.27 ;
    END
  END dout[69]
  PIN dout[6]
    DIRECTION OUTPUT ;
    USE SIGNAL ;
    PORT
      LAYER metal10 ;
        RECT  1074.9 788.47 1075.7 789.27 ;
    END
  END dout[6]
  PIN dout[70]
    DIRECTION OUTPUT ;
    USE SIGNAL ;
    PORT
      LAYER metal10 ;
        RECT  1087.7 804.47 1088.5 805.27 ;
    END
  END dout[70]
  PIN dout[71]
    DIRECTION OUTPUT ;
    USE SIGNAL ;
    PORT
      LAYER metal10 ;
        RECT  1090.9 804.47 1091.7 805.27 ;
    END
  END dout[71]
  PIN dout[72]
    DIRECTION OUTPUT ;
    USE SIGNAL ;
    PORT
      LAYER metal10 ;
        RECT  1055.7 807.67 1056.5 808.47 ;
    END
  END dout[72]
  PIN dout[73]
    DIRECTION OUTPUT ;
    USE SIGNAL ;
    PORT
      LAYER metal10 ;
        RECT  1058.9 807.67 1059.7 808.47 ;
    END
  END dout[73]
  PIN dout[74]
    DIRECTION OUTPUT ;
    USE SIGNAL ;
    PORT
      LAYER metal10 ;
        RECT  1062.09 807.67 1062.89 808.47 ;
    END
  END dout[74]
  PIN dout[75]
    DIRECTION OUTPUT ;
    USE SIGNAL ;
    PORT
      LAYER metal10 ;
        RECT  1065.29 807.67 1066.09 808.47 ;
    END
  END dout[75]
  PIN dout[76]
    DIRECTION OUTPUT ;
    USE SIGNAL ;
    PORT
      LAYER metal10 ;
        RECT  1068.49 807.67 1069.29 808.47 ;
    END
  END dout[76]
  PIN dout[77]
    DIRECTION OUTPUT ;
    USE SIGNAL ;
    PORT
      LAYER metal10 ;
        RECT  1071.7 807.67 1072.5 808.47 ;
    END
  END dout[77]
  PIN dout[78]
    DIRECTION OUTPUT ;
    USE SIGNAL ;
    PORT
      LAYER metal10 ;
        RECT  1074.9 807.67 1075.7 808.47 ;
    END
  END dout[78]
  PIN dout[79]
    DIRECTION OUTPUT ;
    USE SIGNAL ;
    PORT
      LAYER metal10 ;
        RECT  1078.09 807.67 1078.89 808.47 ;
    END
  END dout[79]
  PIN dout[7]
    DIRECTION OUTPUT ;
    USE SIGNAL ;
    PORT
      LAYER metal10 ;
        RECT  1078.09 788.47 1078.89 789.27 ;
    END
  END dout[7]
  PIN dout[80]
    DIRECTION OUTPUT ;
    USE SIGNAL ;
    PORT
      LAYER metal10 ;
        RECT  1081.29 807.67 1082.09 808.47 ;
    END
  END dout[80]
  PIN dout[81]
    DIRECTION OUTPUT ;
    USE SIGNAL ;
    PORT
      LAYER metal10 ;
        RECT  1084.49 807.67 1085.29 808.47 ;
    END
  END dout[81]
  PIN dout[82]
    DIRECTION OUTPUT ;
    USE SIGNAL ;
    PORT
      LAYER metal10 ;
        RECT  1087.7 807.67 1088.5 808.47 ;
    END
  END dout[82]
  PIN dout[83]
    DIRECTION OUTPUT ;
    USE SIGNAL ;
    PORT
      LAYER metal10 ;
        RECT  1090.9 807.67 1091.7 808.47 ;
    END
  END dout[83]
  PIN dout[84]
    DIRECTION OUTPUT ;
    USE SIGNAL ;
    PORT
      LAYER metal10 ;
        RECT  1055.7 810.87 1056.5 811.67 ;
    END
  END dout[84]
  PIN dout[85]
    DIRECTION OUTPUT ;
    USE SIGNAL ;
    PORT
      LAYER metal10 ;
        RECT  1058.9 810.87 1059.7 811.67 ;
    END
  END dout[85]
  PIN dout[86]
    DIRECTION OUTPUT ;
    USE SIGNAL ;
    PORT
      LAYER metal10 ;
        RECT  1062.09 810.87 1062.89 811.67 ;
    END
  END dout[86]
  PIN dout[87]
    DIRECTION OUTPUT ;
    USE SIGNAL ;
    PORT
      LAYER metal10 ;
        RECT  1065.29 810.87 1066.09 811.67 ;
    END
  END dout[87]
  PIN dout[88]
    DIRECTION OUTPUT ;
    USE SIGNAL ;
    PORT
      LAYER metal10 ;
        RECT  1068.49 810.87 1069.29 811.67 ;
    END
  END dout[88]
  PIN dout[89]
    DIRECTION OUTPUT ;
    USE SIGNAL ;
    PORT
      LAYER metal10 ;
        RECT  1071.7 810.87 1072.5 811.67 ;
    END
  END dout[89]
  PIN dout[8]
    DIRECTION OUTPUT ;
    USE SIGNAL ;
    PORT
      LAYER metal10 ;
        RECT  1081.29 788.47 1082.09 789.27 ;
    END
  END dout[8]
  PIN dout[90]
    DIRECTION OUTPUT ;
    USE SIGNAL ;
    PORT
      LAYER metal10 ;
        RECT  1074.9 810.87 1075.7 811.67 ;
    END
  END dout[90]
  PIN dout[91]
    DIRECTION OUTPUT ;
    USE SIGNAL ;
    PORT
      LAYER metal10 ;
        RECT  1078.09 810.87 1078.89 811.67 ;
    END
  END dout[91]
  PIN dout[92]
    DIRECTION OUTPUT ;
    USE SIGNAL ;
    PORT
      LAYER metal10 ;
        RECT  1081.29 810.87 1082.09 811.67 ;
    END
  END dout[92]
  PIN dout[93]
    DIRECTION OUTPUT ;
    USE SIGNAL ;
    PORT
      LAYER metal10 ;
        RECT  1084.49 810.87 1085.29 811.67 ;
    END
  END dout[93]
  PIN dout[94]
    DIRECTION OUTPUT ;
    USE SIGNAL ;
    PORT
      LAYER metal10 ;
        RECT  1087.7 810.87 1088.5 811.67 ;
    END
  END dout[94]
  PIN dout[95]
    DIRECTION OUTPUT ;
    USE SIGNAL ;
    PORT
      LAYER metal10 ;
        RECT  1090.9 810.87 1091.7 811.67 ;
    END
  END dout[95]
  PIN dout[96]
    DIRECTION OUTPUT ;
    USE SIGNAL ;
    PORT
      LAYER metal10 ;
        RECT  1055.7 814.07 1056.5 814.87 ;
    END
  END dout[96]
  PIN dout[97]
    DIRECTION OUTPUT ;
    USE SIGNAL ;
    PORT
      LAYER metal10 ;
        RECT  1058.9 814.07 1059.7 814.87 ;
    END
  END dout[97]
  PIN dout[98]
    DIRECTION OUTPUT ;
    USE SIGNAL ;
    PORT
      LAYER metal10 ;
        RECT  1062.09 814.07 1062.89 814.87 ;
    END
  END dout[98]
  PIN dout[99]
    DIRECTION OUTPUT ;
    USE SIGNAL ;
    PORT
      LAYER metal10 ;
        RECT  1065.29 814.07 1066.09 814.87 ;
    END
  END dout[99]
  PIN dout[9]
    DIRECTION OUTPUT ;
    USE SIGNAL ;
    PORT
      LAYER metal10 ;
        RECT  1084.49 788.47 1085.29 789.27 ;
    END
  END dout[9]
  PIN ready
    DIRECTION OUTPUT ;
    USE SIGNAL ;
    PORT
      LAYER metal10 ;
        RECT  1.295 55.67 2.095 56.47 ;
    END
  END ready
  PIN valid
    DIRECTION OUTPUT ;
    USE SIGNAL ;
    PORT
      LAYER metal10 ;
        RECT  1.295 68.47 2.095 69.27 ;
    END
  END valid
  PIN req
    DIRECTION INPUT ;
    USE SIGNAL ;
    PORT
      LAYER metal10 ;
        RECT  1.295 58.87 2.095 59.67 ;
    END
  END req
  PIN reset
    DIRECTION INPUT ;
    USE SIGNAL ;
    PORT
      LAYER metal10 ;
        RECT  1.295 62.07 2.095 62.87 ;
    END
  END reset
  PIN take
    DIRECTION INPUT ;
    USE SIGNAL ;
    PORT
      LAYER metal10 ;
        RECT  1.295 65.27 2.095 66.07 ;
    END
  END take
  PIN wr
    DIRECTION INPUT ;
    USE SIGNAL ;
    PORT
      LAYER metal10 ;
        RECT  1.295 71.67 2.095 72.47 ;
    END
  END wr
  PIN VDD
    DIRECTION INOUT ;
    USE POWER ;
    PORT
      LAYER metal7 ;
        RECT  20.14 1567.3 1589.92 1568.7 ;
        RECT  20.14 1537.3 1589.92 1538.7 ;
        RECT  20.14 1507.3 1589.92 1508.7 ;
        RECT  20.14 1477.3 1589.92 1478.7 ;
        RECT  20.14 1447.3 1589.92 1448.7 ;
        RECT  20.14 1417.3 1589.92 1418.7 ;
        RECT  20.14 1387.3 1589.92 1388.7 ;
        RECT  20.14 1357.3 1589.92 1358.7 ;
        RECT  20.14 1327.3 1589.92 1328.7 ;
        RECT  20.14 1297.3 1589.92 1298.7 ;
        RECT  20.14 1267.3 1589.92 1268.7 ;
        RECT  20.14 1237.3 1589.92 1238.7 ;
        RECT  20.14 1207.3 1589.92 1208.7 ;
        RECT  20.14 1177.3 1589.92 1178.7 ;
        RECT  20.14 1147.3 1589.92 1148.7 ;
        RECT  20.14 1117.3 1589.92 1118.7 ;
        RECT  20.14 1087.3 1589.92 1088.7 ;
        RECT  20.14 1057.3 1589.92 1058.7 ;
        RECT  20.14 1027.3 1589.92 1028.7 ;
        RECT  20.14 997.3 1589.92 998.7 ;
        RECT  20.14 967.3 1589.92 968.7 ;
        RECT  20.14 937.3 1589.92 938.7 ;
        RECT  20.14 907.3 1589.92 908.7 ;
        RECT  20.14 877.3 1589.92 878.7 ;
        RECT  20.14 847.3 1589.92 848.7 ;
        RECT  20.14 817.3 1589.92 818.7 ;
        RECT  20.14 787.3 1589.92 788.7 ;
        RECT  20.14 757.3 1589.92 758.7 ;
        RECT  20.14 727.3 1589.92 728.7 ;
        RECT  20.14 697.3 1589.92 698.7 ;
        RECT  20.14 667.3 1589.92 668.7 ;
        RECT  20.14 637.3 1589.92 638.7 ;
        RECT  20.14 607.3 1589.92 608.7 ;
        RECT  20.14 577.3 1589.92 578.7 ;
        RECT  20.14 547.3 1589.92 548.7 ;
        RECT  20.14 517.3 1589.92 518.7 ;
        RECT  20.14 487.3 1589.92 488.7 ;
        RECT  20.14 457.3 1589.92 458.7 ;
        RECT  20.14 427.3 1589.92 428.7 ;
        RECT  20.14 397.3 1589.92 398.7 ;
        RECT  20.14 367.3 1589.92 368.7 ;
        RECT  20.14 337.3 1589.92 338.7 ;
        RECT  20.14 307.3 1589.92 308.7 ;
        RECT  20.14 277.3 1589.92 278.7 ;
        RECT  20.14 247.3 1589.92 248.7 ;
        RECT  20.14 217.3 1589.92 218.7 ;
        RECT  20.14 187.3 1589.92 188.7 ;
        RECT  20.14 157.3 1589.92 158.7 ;
        RECT  20.14 127.3 1589.92 128.7 ;
        RECT  20.14 97.3 1589.92 98.7 ;
        RECT  20.14 67.3 1589.92 68.7 ;
        RECT  20.14 37.3 1589.92 38.7 ;
    END
  END VDD
  PIN VSS
    DIRECTION INOUT ;
    USE GROUND ;
    PORT
      LAYER metal7 ;
        RECT  20.14 1582.3 1589.92 1583.7 ;
        RECT  20.14 1552.3 1589.92 1553.7 ;
        RECT  20.14 1522.3 1589.92 1523.7 ;
        RECT  20.14 1492.3 1589.92 1493.7 ;
        RECT  20.14 1462.3 1589.92 1463.7 ;
        RECT  20.14 1432.3 1589.92 1433.7 ;
        RECT  20.14 1402.3 1589.92 1403.7 ;
        RECT  20.14 1372.3 1589.92 1373.7 ;
        RECT  20.14 1342.3 1589.92 1343.7 ;
        RECT  20.14 1312.3 1589.92 1313.7 ;
        RECT  20.14 1282.3 1589.92 1283.7 ;
        RECT  20.14 1252.3 1589.92 1253.7 ;
        RECT  20.14 1222.3 1589.92 1223.7 ;
        RECT  20.14 1192.3 1589.92 1193.7 ;
        RECT  20.14 1162.3 1589.92 1163.7 ;
        RECT  20.14 1132.3 1589.92 1133.7 ;
        RECT  20.14 1102.3 1589.92 1103.7 ;
        RECT  20.14 1072.3 1589.92 1073.7 ;
        RECT  20.14 1042.3 1589.92 1043.7 ;
        RECT  20.14 1012.3 1589.92 1013.7 ;
        RECT  20.14 982.3 1589.92 983.7 ;
        RECT  20.14 952.3 1589.92 953.7 ;
        RECT  20.14 922.3 1589.92 923.7 ;
        RECT  20.14 892.3 1589.92 893.7 ;
        RECT  20.14 862.3 1589.92 863.7 ;
        RECT  20.14 832.3 1589.92 833.7 ;
        RECT  20.14 802.3 1589.92 803.7 ;
        RECT  20.14 772.3 1589.92 773.7 ;
        RECT  20.14 742.3 1589.92 743.7 ;
        RECT  20.14 712.3 1589.92 713.7 ;
        RECT  20.14 682.3 1589.92 683.7 ;
        RECT  20.14 652.3 1589.92 653.7 ;
        RECT  20.14 622.3 1589.92 623.7 ;
        RECT  20.14 592.3 1589.92 593.7 ;
        RECT  20.14 562.3 1589.92 563.7 ;
        RECT  20.14 532.3 1589.92 533.7 ;
        RECT  20.14 502.3 1589.92 503.7 ;
        RECT  20.14 472.3 1589.92 473.7 ;
        RECT  20.14 442.3 1589.92 443.7 ;
        RECT  20.14 412.3 1589.92 413.7 ;
        RECT  20.14 382.3 1589.92 383.7 ;
        RECT  20.14 352.3 1589.92 353.7 ;
        RECT  20.14 322.3 1589.92 323.7 ;
        RECT  20.14 292.3 1589.92 293.7 ;
        RECT  20.14 262.3 1589.92 263.7 ;
        RECT  20.14 232.3 1589.92 233.7 ;
        RECT  20.14 202.3 1589.92 203.7 ;
        RECT  20.14 172.3 1589.92 173.7 ;
        RECT  20.14 142.3 1589.92 143.7 ;
        RECT  20.14 112.3 1589.92 113.7 ;
        RECT  20.14 82.3 1589.92 83.7 ;
        RECT  20.14 52.3 1589.92 53.7 ;
        RECT  20.14 22.3 1589.92 23.7 ;
    END
  END VSS
  OBS
    LAYER metal1 ;
     RECT  0.495 20.47 1589.92 1589.28 ;
    LAYER metal2 ;
     RECT  0.495 20.47 1589.92 1589.28 ;
    LAYER metal3 ;
     RECT  0.495 20.47 1589.92 1589.28 ;
    LAYER metal4 ;
     RECT  0.495 20.47 1589.92 1589.28 ;
    LAYER metal5 ;
     RECT  0.495 20.47 1589.92 1589.28 ;
    LAYER metal6 ;
     RECT  0.495 20.47 1589.92 1589.28 ;
    LAYER metal7 ;
     RECT  0.495 20.47 1589.92 1589.28 ;
    LAYER metal8 ;
     RECT  0.495 20.47 1589.92 1589.28 ;
    LAYER metal9 ;
     RECT  0.495 20.47 1589.92 1589.28 ;
    LAYER metal10 ;
     RECT  0.495 20.47 1589.92 1589.28 ;
  END
END block_v1_s16k
END LIBRARY
